VERSION 5.7 ;
  NOWIREEXTENSIONATPIN ON ;
  DIVIDERCHAR "/" ;
  BUSBITCHARS "[]" ;
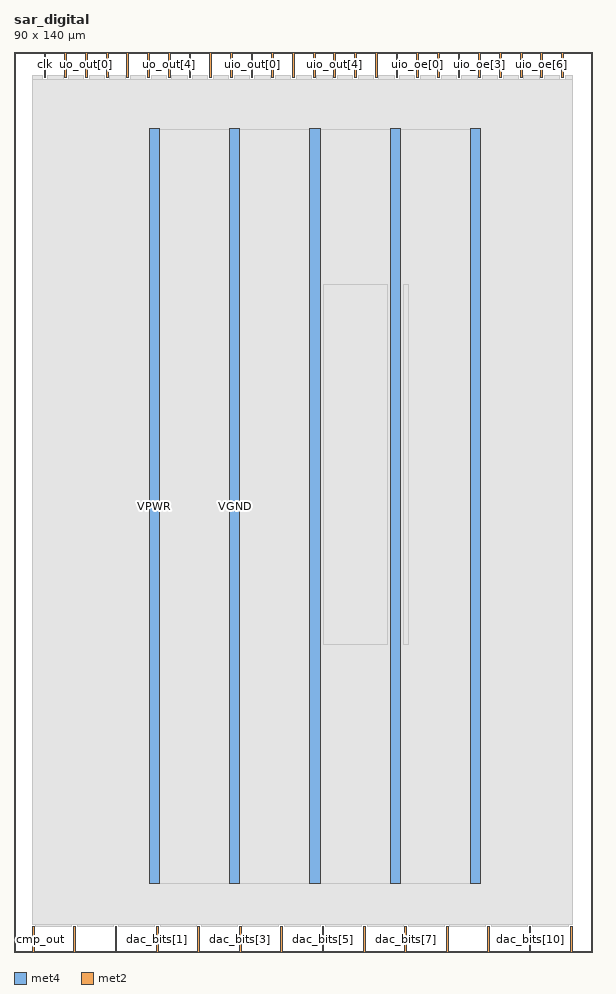
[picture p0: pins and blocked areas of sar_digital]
MACRO sar_digital
  CLASS BLOCK ;
  FOREIGN sar_digital ;
  ORIGIN 0.000 0.000 ;
  SIZE 90.000 BY 140.000 ;
  PIN VGND
    DIRECTION INOUT ;
    USE GROUND ;
    PORT
      LAYER met4 ;
        RECT 33.540 10.640 35.140 128.080 ;
    END
    PORT
      LAYER met4 ;
        RECT 58.540 10.640 60.140 128.080 ;
    END
  END VGND
  PIN VPWR
    DIRECTION INOUT ;
    USE POWER ;
    PORT
      LAYER met4 ;
        RECT 21.040 10.640 22.640 128.080 ;
    END
    PORT
      LAYER met4 ;
        RECT 46.040 10.640 47.640 128.080 ;
    END
    PORT
      LAYER met4 ;
        RECT 71.040 10.640 72.640 128.080 ;
    END
  END VPWR
  PIN clk
    DIRECTION INPUT ;
    USE SIGNAL ;
    ANTENNAGATEAREA 0.852000 ;
    PORT
      LAYER met2 ;
        RECT 4.690 136.000 4.970 140.000 ;
    END
  END clk
  PIN cmp_out
    DIRECTION INPUT ;
    USE SIGNAL ;
    ANTENNAGATEAREA 0.213000 ;
    PORT
      LAYER met2 ;
        RECT 2.850 0.000 3.130 4.000 ;
    END
  END cmp_out
  PIN dac_bits[0]
    DIRECTION OUTPUT TRISTATE ;
    USE SIGNAL ;
    ANTENNADIFFAREA 0.795200 ;
    PORT
      LAYER met2 ;
        RECT 15.730 0.000 16.010 4.000 ;
    END
  END dac_bits[0]
  PIN dac_bits[10]
    DIRECTION OUTPUT TRISTATE ;
    USE SIGNAL ;
    ANTENNADIFFAREA 0.795200 ;
    PORT
      LAYER met2 ;
        RECT 80.130 0.000 80.410 4.000 ;
    END
  END dac_bits[10]
  PIN dac_bits[11]
    DIRECTION OUTPUT TRISTATE ;
    USE SIGNAL ;
    ANTENNADIFFAREA 0.795200 ;
    PORT
      LAYER met2 ;
        RECT 86.570 0.000 86.850 4.000 ;
    END
  END dac_bits[11]
  PIN dac_bits[1]
    DIRECTION OUTPUT TRISTATE ;
    USE SIGNAL ;
    ANTENNADIFFAREA 0.795200 ;
    PORT
      LAYER met2 ;
        RECT 22.170 0.000 22.450 4.000 ;
    END
  END dac_bits[1]
  PIN dac_bits[2]
    DIRECTION OUTPUT TRISTATE ;
    USE SIGNAL ;
    ANTENNADIFFAREA 0.795200 ;
    PORT
      LAYER met2 ;
        RECT 28.610 0.000 28.890 4.000 ;
    END
  END dac_bits[2]
  PIN dac_bits[3]
    DIRECTION OUTPUT TRISTATE ;
    USE SIGNAL ;
    ANTENNADIFFAREA 0.795200 ;
    PORT
      LAYER met2 ;
        RECT 35.050 0.000 35.330 4.000 ;
    END
  END dac_bits[3]
  PIN dac_bits[4]
    DIRECTION OUTPUT TRISTATE ;
    USE SIGNAL ;
    ANTENNADIFFAREA 0.795200 ;
    PORT
      LAYER met2 ;
        RECT 41.490 0.000 41.770 4.000 ;
    END
  END dac_bits[4]
  PIN dac_bits[5]
    DIRECTION OUTPUT TRISTATE ;
    USE SIGNAL ;
    ANTENNADIFFAREA 0.795200 ;
    PORT
      LAYER met2 ;
        RECT 47.930 0.000 48.210 4.000 ;
    END
  END dac_bits[5]
  PIN dac_bits[6]
    DIRECTION OUTPUT TRISTATE ;
    USE SIGNAL ;
    ANTENNADIFFAREA 0.795200 ;
    PORT
      LAYER met2 ;
        RECT 54.370 0.000 54.650 4.000 ;
    END
  END dac_bits[6]
  PIN dac_bits[7]
    DIRECTION OUTPUT TRISTATE ;
    USE SIGNAL ;
    ANTENNADIFFAREA 0.795200 ;
    PORT
      LAYER met2 ;
        RECT 60.810 0.000 61.090 4.000 ;
    END
  END dac_bits[7]
  PIN dac_bits[8]
    DIRECTION OUTPUT TRISTATE ;
    USE SIGNAL ;
    ANTENNADIFFAREA 0.795200 ;
    PORT
      LAYER met2 ;
        RECT 67.250 0.000 67.530 4.000 ;
    END
  END dac_bits[8]
  PIN dac_bits[9]
    DIRECTION OUTPUT TRISTATE ;
    USE SIGNAL ;
    ANTENNADIFFAREA 0.795200 ;
    PORT
      LAYER met2 ;
        RECT 73.690 0.000 73.970 4.000 ;
    END
  END dac_bits[9]
  PIN rst_n
    DIRECTION INPUT ;
    USE SIGNAL ;
    ANTENNAGATEAREA 0.213000 ;
    PORT
      LAYER met2 ;
        RECT 7.910 136.000 8.190 140.000 ;
    END
  END rst_n
  PIN sample
    DIRECTION OUTPUT TRISTATE ;
    USE SIGNAL ;
    ANTENNADIFFAREA 0.795200 ;
    PORT
      LAYER met2 ;
        RECT 9.290 0.000 9.570 4.000 ;
    END
  END sample
  PIN uio_oe[0]
    DIRECTION OUTPUT TRISTATE ;
    USE SIGNAL ;
    PORT
      LAYER met2 ;
        RECT 62.650 136.000 62.930 140.000 ;
    END
  END uio_oe[0]
  PIN uio_oe[1]
    DIRECTION OUTPUT TRISTATE ;
    USE SIGNAL ;
    PORT
      LAYER met2 ;
        RECT 65.870 136.000 66.150 140.000 ;
    END
  END uio_oe[1]
  PIN uio_oe[2]
    DIRECTION OUTPUT TRISTATE ;
    USE SIGNAL ;
    PORT
      LAYER met2 ;
        RECT 69.090 136.000 69.370 140.000 ;
    END
  END uio_oe[2]
  PIN uio_oe[3]
    DIRECTION OUTPUT TRISTATE ;
    USE SIGNAL ;
    PORT
      LAYER met2 ;
        RECT 72.310 136.000 72.590 140.000 ;
    END
  END uio_oe[3]
  PIN uio_oe[4]
    DIRECTION OUTPUT TRISTATE ;
    USE SIGNAL ;
    PORT
      LAYER met2 ;
        RECT 75.530 136.000 75.810 140.000 ;
    END
  END uio_oe[4]
  PIN uio_oe[5]
    DIRECTION OUTPUT TRISTATE ;
    USE SIGNAL ;
    PORT
      LAYER met2 ;
        RECT 78.750 136.000 79.030 140.000 ;
    END
  END uio_oe[5]
  PIN uio_oe[6]
    DIRECTION OUTPUT TRISTATE ;
    USE SIGNAL ;
    PORT
      LAYER met2 ;
        RECT 81.970 136.000 82.250 140.000 ;
    END
  END uio_oe[6]
  PIN uio_oe[7]
    DIRECTION OUTPUT TRISTATE ;
    USE SIGNAL ;
    PORT
      LAYER met2 ;
        RECT 85.190 136.000 85.470 140.000 ;
    END
  END uio_oe[7]
  PIN uio_out[0]
    DIRECTION OUTPUT TRISTATE ;
    USE SIGNAL ;
    ANTENNADIFFAREA 0.795200 ;
    PORT
      LAYER met2 ;
        RECT 36.890 136.000 37.170 140.000 ;
    END
  END uio_out[0]
  PIN uio_out[1]
    DIRECTION OUTPUT TRISTATE ;
    USE SIGNAL ;
    ANTENNADIFFAREA 0.795200 ;
    PORT
      LAYER met2 ;
        RECT 40.110 136.000 40.390 140.000 ;
    END
  END uio_out[1]
  PIN uio_out[2]
    DIRECTION OUTPUT TRISTATE ;
    USE SIGNAL ;
    ANTENNADIFFAREA 0.795200 ;
    PORT
      LAYER met2 ;
        RECT 43.330 136.000 43.610 140.000 ;
    END
  END uio_out[2]
  PIN uio_out[3]
    DIRECTION OUTPUT TRISTATE ;
    USE SIGNAL ;
    ANTENNADIFFAREA 0.795200 ;
    PORT
      LAYER met2 ;
        RECT 46.550 136.000 46.830 140.000 ;
    END
  END uio_out[3]
  PIN uio_out[4]
    DIRECTION OUTPUT TRISTATE ;
    USE SIGNAL ;
    ANTENNADIFFAREA 0.795200 ;
    PORT
      LAYER met2 ;
        RECT 49.770 136.000 50.050 140.000 ;
    END
  END uio_out[4]
  PIN uio_out[5]
    DIRECTION OUTPUT TRISTATE ;
    USE SIGNAL ;
    PORT
      LAYER met2 ;
        RECT 52.990 136.000 53.270 140.000 ;
    END
  END uio_out[5]
  PIN uio_out[6]
    DIRECTION OUTPUT TRISTATE ;
    USE SIGNAL ;
    PORT
      LAYER met2 ;
        RECT 56.210 136.000 56.490 140.000 ;
    END
  END uio_out[6]
  PIN uio_out[7]
    DIRECTION OUTPUT TRISTATE ;
    USE SIGNAL ;
    PORT
      LAYER met2 ;
        RECT 59.430 136.000 59.710 140.000 ;
    END
  END uio_out[7]
  PIN uo_out[0]
    DIRECTION OUTPUT TRISTATE ;
    USE SIGNAL ;
    ANTENNADIFFAREA 0.795200 ;
    PORT
      LAYER met2 ;
        RECT 11.130 136.000 11.410 140.000 ;
    END
  END uo_out[0]
  PIN uo_out[1]
    DIRECTION OUTPUT TRISTATE ;
    USE SIGNAL ;
    ANTENNADIFFAREA 0.795200 ;
    PORT
      LAYER met2 ;
        RECT 14.350 136.000 14.630 140.000 ;
    END
  END uo_out[1]
  PIN uo_out[2]
    DIRECTION OUTPUT TRISTATE ;
    USE SIGNAL ;
    ANTENNADIFFAREA 0.795200 ;
    PORT
      LAYER met2 ;
        RECT 17.570 136.000 17.850 140.000 ;
    END
  END uo_out[2]
  PIN uo_out[3]
    DIRECTION OUTPUT TRISTATE ;
    USE SIGNAL ;
    ANTENNADIFFAREA 0.795200 ;
    PORT
      LAYER met2 ;
        RECT 20.790 136.000 21.070 140.000 ;
    END
  END uo_out[3]
  PIN uo_out[4]
    DIRECTION OUTPUT TRISTATE ;
    USE SIGNAL ;
    ANTENNADIFFAREA 0.795200 ;
    PORT
      LAYER met2 ;
        RECT 24.010 136.000 24.290 140.000 ;
    END
  END uo_out[4]
  PIN uo_out[5]
    DIRECTION OUTPUT TRISTATE ;
    USE SIGNAL ;
    ANTENNADIFFAREA 0.795200 ;
    PORT
      LAYER met2 ;
        RECT 27.230 136.000 27.510 140.000 ;
    END
  END uo_out[5]
  PIN uo_out[6]
    DIRECTION OUTPUT TRISTATE ;
    USE SIGNAL ;
    ANTENNADIFFAREA 0.795200 ;
    PORT
      LAYER met2 ;
        RECT 30.450 136.000 30.730 140.000 ;
    END
  END uo_out[6]
  PIN uo_out[7]
    DIRECTION OUTPUT TRISTATE ;
    USE SIGNAL ;
    ANTENNADIFFAREA 0.795200 ;
    PORT
      LAYER met2 ;
        RECT 33.670 136.000 33.950 140.000 ;
    END
  END uo_out[7]
  OBS
      LAYER li1 ;
        RECT 5.520 10.795 84.180 127.925 ;
      LAYER met1 ;
        RECT 2.830 10.640 86.870 128.080 ;
      LAYER met2 ;
        RECT 2.860 135.720 4.410 136.410 ;
        RECT 5.250 135.720 7.630 136.410 ;
        RECT 8.470 135.720 10.850 136.410 ;
        RECT 11.690 135.720 14.070 136.410 ;
        RECT 14.910 135.720 17.290 136.410 ;
        RECT 18.130 135.720 20.510 136.410 ;
        RECT 21.350 135.720 23.730 136.410 ;
        RECT 24.570 135.720 26.950 136.410 ;
        RECT 27.790 135.720 30.170 136.410 ;
        RECT 31.010 135.720 33.390 136.410 ;
        RECT 34.230 135.720 36.610 136.410 ;
        RECT 37.450 135.720 39.830 136.410 ;
        RECT 40.670 135.720 43.050 136.410 ;
        RECT 43.890 135.720 46.270 136.410 ;
        RECT 47.110 135.720 49.490 136.410 ;
        RECT 50.330 135.720 52.710 136.410 ;
        RECT 53.550 135.720 55.930 136.410 ;
        RECT 56.770 135.720 59.150 136.410 ;
        RECT 59.990 135.720 62.370 136.410 ;
        RECT 63.210 135.720 65.590 136.410 ;
        RECT 66.430 135.720 68.810 136.410 ;
        RECT 69.650 135.720 72.030 136.410 ;
        RECT 72.870 135.720 75.250 136.410 ;
        RECT 76.090 135.720 78.470 136.410 ;
        RECT 79.310 135.720 81.690 136.410 ;
        RECT 82.530 135.720 84.910 136.410 ;
        RECT 85.750 135.720 86.840 136.410 ;
        RECT 2.860 4.280 86.840 135.720 ;
        RECT 3.410 4.000 9.010 4.280 ;
        RECT 9.850 4.000 15.450 4.280 ;
        RECT 16.290 4.000 21.890 4.280 ;
        RECT 22.730 4.000 28.330 4.280 ;
        RECT 29.170 4.000 34.770 4.280 ;
        RECT 35.610 4.000 41.210 4.280 ;
        RECT 42.050 4.000 47.650 4.280 ;
        RECT 48.490 4.000 54.090 4.280 ;
        RECT 54.930 4.000 60.530 4.280 ;
        RECT 61.370 4.000 66.970 4.280 ;
        RECT 67.810 4.000 73.410 4.280 ;
        RECT 74.250 4.000 79.850 4.280 ;
        RECT 80.690 4.000 86.290 4.280 ;
      LAYER met3 ;
        RECT 21.050 10.715 72.630 128.005 ;
      LAYER met4 ;
        RECT 48.135 47.775 58.140 103.865 ;
        RECT 60.540 47.775 61.345 103.865 ;
  END
END sar_digital
END LIBRARY

